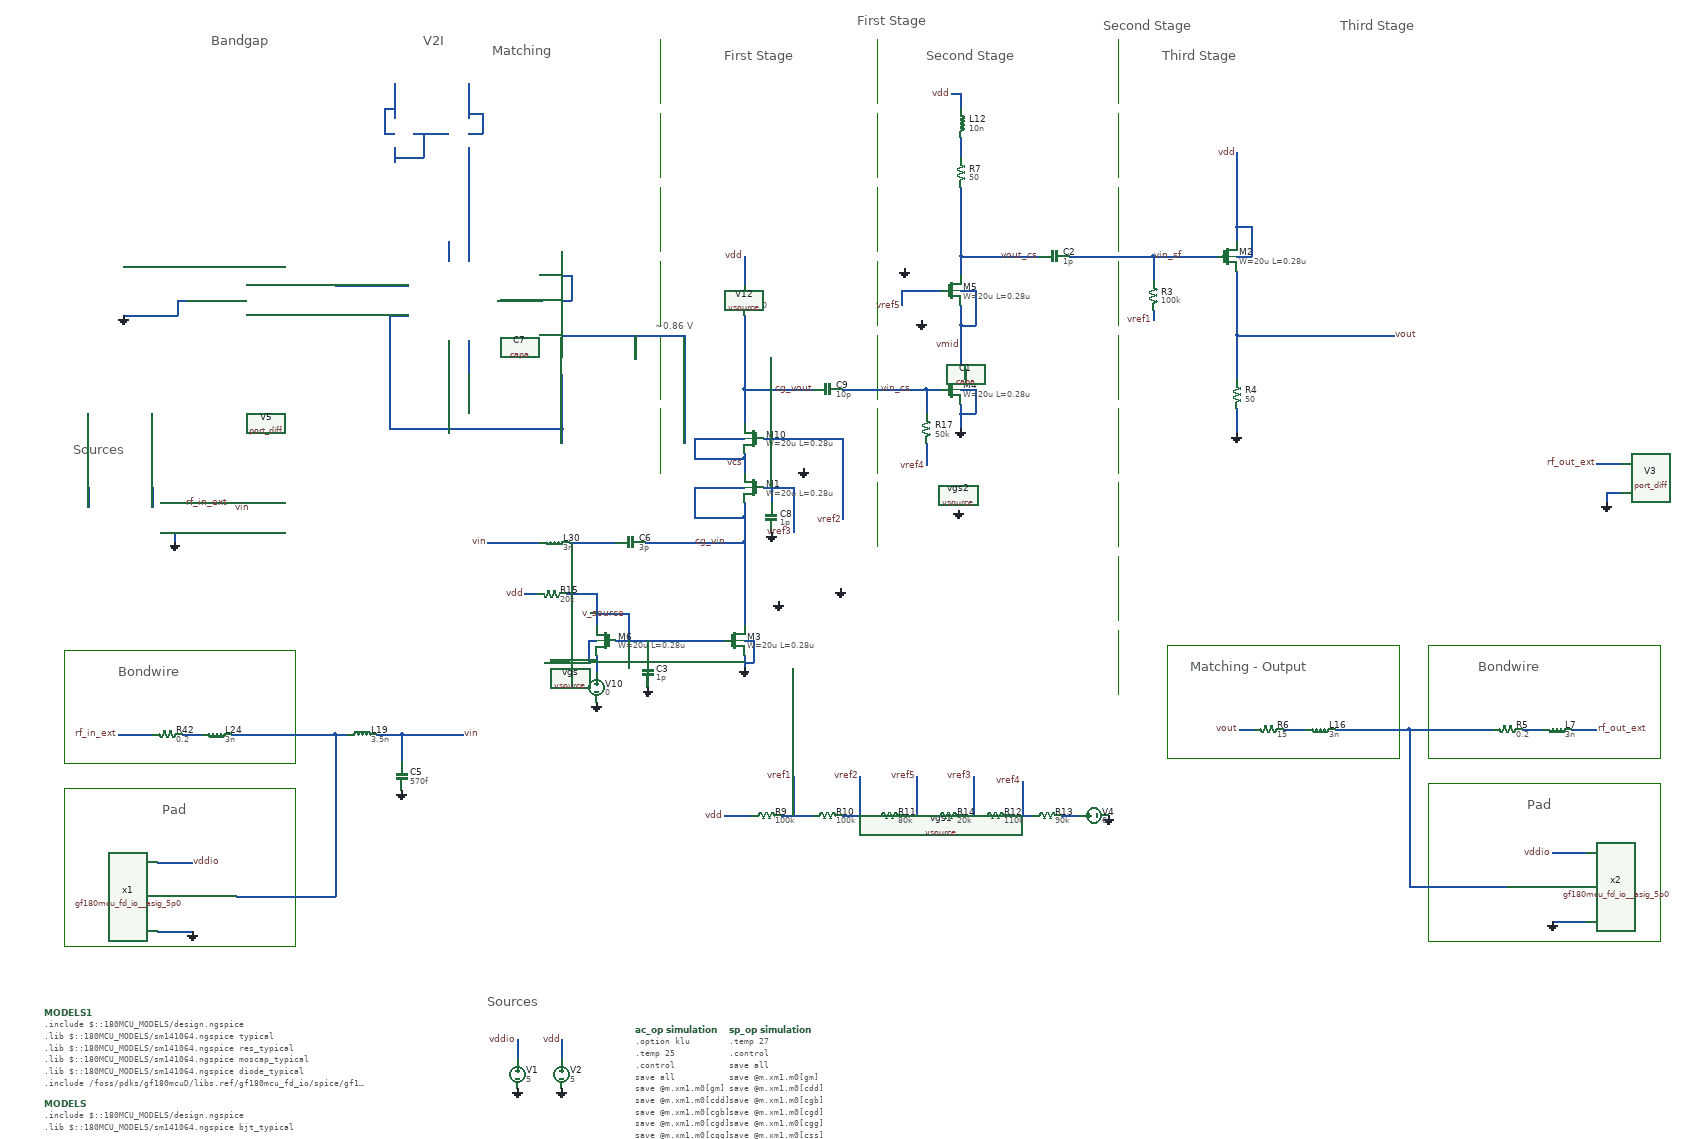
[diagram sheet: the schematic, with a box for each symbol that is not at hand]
v {xschem version=3.4.5 file_version=1.2
}
G {}
K {}
V {}
S {}
E {}
L 4 1330 -2210 1330 -2080 {}
L 4 1330 -2060 1330 -1930 {}
L 4 1330 -1910 1330 -1780 {}
L 4 1330 -1760 1330 -1630 {}
L 4 1330 -1610 1330 -1480 {}
L 4 1330 -2360 1330 -2230 {}
L 4 1770 -2210 1770 -2080 {}
L 4 1770 -2060 1770 -1930 {}
L 4 1770 -1910 1770 -1780 {}
L 4 1770 -1760 1770 -1630 {}
L 4 1770 -1610 1770 -1480 {}
L 4 1770 -1460 1770 -1330 {}
L 4 1770 -2360 1770 -2230 {}
L 4 2260 -2210 2260 -2080 {}
L 4 2260 -2060 2260 -1930 {}
L 4 2260 -1910 2260 -1780 {}
L 4 2260 -1760 2260 -1630 {}
L 4 2260 -1610 2260 -1480 {}
L 4 2260 -2360 2260 -2230 {}
L 4 2260 -1460 2260 -1330 {}
L 4 2260 -1310 2260 -1180 {}
L 4 2260 -1160 2260 -1030 {}
P 4 6 120 -1070 120 -890 590 -890 590 -1120 120 -1120 120 -1070 {}
P 4 6 120 -790 120 -520 590 -520 590 -840 120 -840 120 -790 {}
P 4 6 2890 -1080 2890 -900 3360 -900 3360 -1130 2890 -1130 2890 -1080 {}
P 4 6 2890 -800 2890 -530 3360 -530 3360 -850 2890 -850 2890 -800 {}
P 4 6 2360 -1080 2360 -900 2830 -900 2830 -1130 2360 -1130 2360 -1080 {}
P 4 1 1405 -1355 {}
T {First Stage} 1460 -2340 0 0 0.8 0.8 {}
T {Second Stage} 1870 -2340 0 0 0.8 0.8 {}
T {Third Stage} 2350 -2340 0 0 0.8 0.8 {}
T {Sources} 980 -420 0 0 0.8 0.8 {}
T {Bondwire} 230 -1090 0 0 0.8 0.8 {}
T {Pad} 320 -810 0 0 0.8 0.8 {}
T {Matching} 990 -2350 0 0 0.8 0.8 {}
T {Bondwire} 2990 -1100 0 0 0.8 0.8 {}
T {Pad} 3090 -820 0 0 0.8 0.8 {}
T {Matching - Output} 2405 -1100 0 0 0.8 0.8 {}
N 1040 -330 1040 -290 {lab=vddio}
T {Bandgap} 420 -2370 0 0 0.8 0.8 {}
T {V2I} 850 -2370 0 0 0.8 0.8 {}
T {~0.86 V} 1320 -1790 0 0 0.4 0.4 {}
T {First Stage} 1730 -2410 0 0 0.8 0.8 {}
T {Second Stage} 2230 -2400 0 0 0.8 0.8 {}
T {Third Stage} 2710 -2400 0 0 0.8 0.8 {}
T {Sources} 140 -1540 0 0 0.8 0.8 {}
N 300 -1900 370 -1900 {lab=vdd_5v}
N 240 -1900 300 -1900 {lab=vdd_5v}
N 350 -1830 370 -1830 {lab=0}
N 350 -1830 350 -1810 {lab=0}
N 350 -1810 350 -1800 {lab=0}
N 240 -1800 350 -1800 {lab=0}
N 670 -1860 820 -1860 {lab=vp}
N 900 -1750 900 -1730 {lab=0}
N 940 -1750 940 -1680 {lab=#net1}
N 900 -1950 900 -1910 {lab=vdd_5v}
N 790 -2250 790 -2230 {
lab=vdd_5v}
N 790 -2260 790 -2250 {lab=vdd_5v}
N 780 -1800 820 -1800 {lab=vn}
N 780 -1800 780 -1570 {lab=vn}
N 1000 -1830 1090 -1830 {lab=vref}
N 780 -1570 1130 -1570 {lab=vn}
N 1130 -1930 1130 -1860 {lab=vdd_5v}
N 1130 -1800 1130 -1740 {lab=vdiode}
N 1130 -1680 1130 -1570 {lab=vn}
N 1130 -1570 1130 -1540 {lab=vn}
N 1130 -1760 1380 -1760 {lab=vdiode}
N 1280 -1760 1280 -1710 {lab=vdiode}
N 1380 -1760 1380 -1720 {lab=vdiode}
N 1130 -1830 1150 -1830 {lab=vdd_5v}
N 1150 -1880 1150 -1830 {lab=vdd_5v}
N 1130 -1880 1150 -1880 {lab=vdd_5v}
N 1380 -1720 1380 -1540 {lab=vdiode}
N 830 -2170 900 -2170 {lab=#net2}
N 790 -2230 790 -2200 {lab=vdd_5v}
N 770 -2170 790 -2170 {lab=vdd_5v}
N 770 -2220 770 -2170 {lab=vdd_5v}
N 770 -2220 790 -2220 {lab=vdd_5v}
N 940 -2230 940 -2200 {lab=vdd_5v}
N 940 -2270 940 -2240 {lab=vdd_5v}
N 940 -2240 940 -2230 {lab=vdd_5v}
N 940 -2170 970 -2170 {lab=vdd_5v}
N 970 -2210 970 -2170 {lab=vdd_5v}
N 940 -2210 970 -2210 {lab=vdd_5v}
N 790 -2140 790 -2110 {lab=#net2}
N 850 -2170 850 -2120 {lab=#net2}
N 790 -2120 850 -2120 {lab=#net2}
N 940 -2130 940 -2100 {lab=#net3}
N 940 -2140 940 -2130 {lab=#net3}
N 940 -2100 940 -1910 {lab=#net3}
N 790 -2270 790 -2260 {lab=vdd_5v}
N 300 -1450 300 -1410 {lab=vdd}
N 170 -1450 170 -1410 {lab=vdd_5v}
N 1950 -1690 1950 -1670 {lab=vin
}
N 1500 -1340 1500 -1170 {lab=cg_vin
}
N 1130 -330 1130 -290 {lab=vdd
}
N 1600 -1450 1600 -1360 {lab=vref3
}
N 1540 -1450 1600 -1450 {lab=vref3
}
N 1500 -1920 1500 -1850 {lab=vdd
}
N 1500 -1650 1640 -1650 {lab=cg_vout
}
N 1500 -1800 1500 -1650 {lab=cg_vout
}
N 1700 -1650 1830 -1650 {lab=vin_cs
}
N 1400 -1450 1500 -1450 {lab=cg_vin
}
N 1940 -1600 1940 -1570 {lab=0
}
N 1940 -1650 1970 -1650 {lab=0
}
N 1970 -1650 1970 -1600 {lab=0
}
N 1940 -2160 1940 -2120 {lab=#net1
}
N 1940 -1820 1940 -1780 {lab=vmid
}
N 1940 -1600 1970 -1600 {lab=0
}
N 1940 -1920 2100 -1920 {lab=vout_cs
}
N 1870 -1650 1900 -1650 {lab=vin_cs
}
N 1940 -1780 1940 -1680 {lab=vmid
}
N 1870 -1650 1870 -1600 {lab=vin_cs
}
N 1870 -1540 1870 -1520 {lab=vref4
}
N 1940 -1920 1940 -1880 {lab=vout_cs
}
N 1940 -1850 1970 -1850 {lab=vmid
}
N 1820 -1850 1900 -1850 {lab=vref5
}
N 1820 -1850 1820 -1820 {lab=vref5
}
N 2160 -1920 2310 -1920 {lab=vin_sf
}
N 2330 -1920 2460 -1920 {lab=vin_sf
}
N 2500 -1920 2530 -1920 {lab=vdd
}
N 2500 -1980 2500 -1950 {lab=vdd
spice_ignore=short}
N 2500 -2130 2500 -1980 {lab=vdd
}
N 2330 -1920 2330 -1870 {lab=vin_sf
}
N 2330 -1810 2330 -1790 {lab=vref1
}
N 1940 -2040 1940 -1920 {lab=vout_cs
}
N 1500 -1510 1500 -1480 {lab=vcs
}
N 1400 -1550 1500 -1550 {lab=vcs
}
N 1500 -1650 1500 -1580 {lab=cg_vout
}
N 1540 -1550 1700 -1550 {lab=vref2
}
N 1700 -1550 1700 -1500 {lab=vref2
}
N 1400 -1550 1400 -1510 {lab=vcs
}
N 1400 -1510 1500 -1510 {lab=vcs
}
N 1400 -1450 1400 -1390 {lab=cg_vin
}
N 1400 -1390 1500 -1390 {lab=cg_vin
}
N 1970 -1850 1970 -1780 {lab=vmid
}
N 1940 -1780 1970 -1780 {lab=vmid
}
N 2500 -1610 2500 -1560 {lab=0
}
N 2530 -1980 2530 -1920 {lab=vdd
spice_ignore=short}
N 2500 -1980 2530 -1980 {lab=vdd
}
N 470 -620 670 -620 {lab=#net2
}
N 230 -950 300 -950 {lab=rf_in_ext
}
N 360 -950 400 -950 {lab=#net3
}
N 460 -950 670 -950 {lab=#net2
}
N 315 -1420 365 -1420 {lab=rf_in_ext
}
N 315 -1360 345 -1360 {lab=0
}
N 345 -1360 345 -1340 {lab=0
}
N 1500 -1420 1500 -1390 {lab=cg_vin
}
N 1500 -1390 1500 -1340 {lab=cg_vin
}
N 310 -690 380 -690 {lab=vddio
}
N 310 -550 380 -550 {lab=0
}
N 3080 -960 3120 -960 {lab=#net4
}
N 3180 -960 3230 -960 {lab=rf_out_ext
}
N 3140 -710 3210 -710 {lab=vddio
}
N 3140 -570 3210 -570 {lab=0
}
N 3230 -1500 3280 -1500 {lab=rf_out_ext
}
N 3250 -1440 3280 -1440 {lab=0
}
N 3250 -1440 3250 -1420 {lab=0
}
N 1940 -2230 1940 -2220 {lab=vdd
}
N 1920 -2250 1940 -2250 {lab=vdd
}
N 2500 -1890 2500 -1760 {lab=vout
}
N 2500 -1760 2500 -1670 {lab=vout
}
N 2500 -1760 2820 -1760 {lab=vout
}
N 2850 -640 3050 -640 {lab=#net5
}
N 2700 -960 2850 -960 {lab=#net5
}
N 2595 -960 2640 -960 {lab=#net6
}
N 2505 -960 2535 -960 {lab=vout
}
N 2850 -960 3020 -960 {lab=#net5
}
N 2850 -960 2850 -640 {lab=#net5
}
N 670 -950 695 -950 {lab=#net2
}
N 670 -950 670 -620 {lab=#net2
}
N 805 -950 805 -895 {lab=vin
}
N 805 -950 930 -950 {lab=vin
}
N 1940 -1620 1940 -1600 {lab=0
}
N 1830 -1650 1870 -1650 {lab=vin_cs
}
N 2310 -1920 2330 -1920 {lab=vin_sf
}
N 1500 -1520 1500 -1510 {lab=vcs
}
N 1940 -2060 1940 -2040 {lab=vout_cs
}
N 1940 -2250 1940 -2230 {lab=vdd
}
N 755 -950 805 -950 {lab=vin
}
N 1500 -1110 1500 -1085 {lab=0
}
N 1500 -1140 1520 -1140 {lab=0
}
N 1520 -1140 1520 -1095 {lab=0
}
N 1500 -1095 1520 -1095 {lab=0
}
N 1415 -1140 1460 -1140 {lab=v_source
}
N 1430 -1340 1495 -1340 {lab=cg_vin
}
N 1495 -1340 1500 -1340 {lab=cg_vin
}
N 1240 -1140 1415 -1140 {lab=v_source
}
N 1185 -1140 1200 -1140 {lab=#net7
}
N 1185 -1140 1185 -1100 {lab=#net7
}
N 1185 -1100 1200 -1100 {lab=#net7
}
N 1200 -1210 1200 -1170 {lab=v_source
}
N 1305 -1140 1305 -1105 {lab=v_source
}
N 1200 -1195 1265 -1195 {lab=v_source
}
N 1265 -1195 1265 -1140 {lab=v_source
}
N 1200 -1235 1200 -1210 {lab=v_source
}
N 1140 -1235 1200 -1235 {lab=v_source
}
N 1460 -785 1515 -785 {lab=vdd
}
N 1575 -785 1640 -785 {lab=vref1
}
N 1600 -865 1600 -785 {lab=vref1
}
N 1700 -785 1765 -785 {lab=vref2
}
N 1735 -865 1735 -785 {lab=vref2
}
N 1850 -865 1850 -785 {lab=vref5
}
N 2040 -785 2085 -785 {lab=vref4
}
N 2065 -855 2065 -785 {lab=vref4
}
N 2145 -785 2180 -785 {lab=#net8
}
N 1200 -1110 1200 -1075 {lab=#net7
}
N 1055 -1235 1080 -1235 {lab=vdd
}
N 1700 -1500 1700 -1465 {lab=vref2
}
N 1150 -1340 1150 -1320 {lab=#net9
}
N 1370 -1340 1430 -1340 {lab=cg_vin}
N 1095 -1095 1145 -1095 {lab=#net14
spice_ignore=true}
N 980 -1340 1075 -1340 {lab=vin}
N 1300 -1340 1370 -1340 {lab=cg_vin}
N 1075 -1340 1085 -1340 {lab=vin}
N 1145 -1340 1240 -1340 {lab=#net9}
N 1870 -1520 1870 -1495 {lab=vref4}
N 1700 -1465 1700 -1385 {lab=vref2}
N 1555 -1450 1555 -1420 {lab=vref3}
N 1830 -785 1850 -785 {lab=vref5}
N 1825 -785 1830 -785 {lab=vref5}
N 1850 -785 1885 -785 {lab=vref5}
N 1945 -785 1980 -785 {lab=vref3}
N 1965 -865 1965 -785 {lab=vref3
}
C {title-2.sym} 0 0 0 0 {name=l8 author="Ilir Shala" title="The Silent Owl" rev=1.0 lock=true}
C {vsource.sym} 1040 -260 0 0 {name=V1 value=5 savecurrent=false
}
C {gnd.sym} 380 -550 0 0 {name=l2 lab=0
}
C {lab_pin.sym} 1040 -330 0 0 {name=p10 sig_type=std_logic lab=vddio
}
C {code_shown.sym} 80 -385 0 0 {name=MODELS1 only_toplevel=true
format="tcleval( @value )"
value="
.include $::180MCU_MODELS/design.ngspice
.lib $::180MCU_MODELS/sm141064.ngspice typical
.lib $::180MCU_MODELS/sm141064.ngspice res_typical
.lib $::180MCU_MODELS/sm141064.ngspice moscap_typical
.lib $::180MCU_MODELS/sm141064.ngspice diode_typical
.include /foss/pdks/gf180mcuD/libs.ref/gf180mcu_fd_io/spice/gf180mcu_fd_io.spice
"
spice_ignore=true} C {bandgap.sym} 520 -1760 0 0 {name=x3}
C {gnd.sym} 240 -1800 0 0 {name=l10 lab=0
}
C {devices/code_shown.sym} 80 -200 0 0 {name=MODELS only_toplevel=true
format="tcleval( @value )"
value="
.include $::180MCU_MODELS/design.ngspice
.lib $::180MCU_MODELS/sm141064.ngspice bjt_typical

"}
C {devices/launcher.sym} 1560 -945 0 0 {name=h2
descr="simulate" 
tclcommand="xschem save; xschem netlist; xschem simulate"
}
C {devices/launcher.sym} 1740 -945 0 0 {name=h1
descr="annotate OP" 
tclcommand="set show_hidden_texts 1; xschem annotate_op"
spice_ignore=true}
C {vsource.sym} 1570 -1250 0 0 {name=vgs value=2 savecurrent=false
spice_ignore=true}
C {gnd.sym} 1570 -1220 0 0 {name=l4 lab=0
spice_ignore=true}
C {vsource.sym} 1130 -260 0 0 {name=V2 value=5 savecurrent=false
}
C {gnd.sym} 1130 -230 0 0 {name=l1 lab=0
}
C {res.sym} 1500 -1830 0 0 {name=R1
value=500
footprint=1206
device=resistor
m=1
}
C {symbols/nfet_03v3.sym} 1520 -1450 0 1 {name=M1
L=0.28u
W=20u
nf=1
m=8
ad="'int((nf+1)/2) * W/nf * 0.18u'"
pd="'2*int((nf+1)/2) * (W/nf + 0.18u)'"
as="'int((nf+2)/2) * W/nf * 0.18u'"
ps="'2*int((nf+2)/2) * (W/nf + 0.18u)'"
nrd="'0.18u / W'" nrs="'0.18u / W'"
sa=0 sb=0 sd=0
model=nfet_03v3
spiceprefix=X
}
C {lab_pin.sym} 1130 -330 0 0 {name=p6 sig_type=std_logic lab=vdd
}
C {lab_pin.sym} 1500 -1920 0 0 {name=p7 sig_type=std_logic lab=vdd
}
C {lab_wire.sym} 1465 -1340 2 1 {name=p9 sig_type=std_logic lab=cg_vin
}
C {lab_wire.sym} 1560 -1650 2 0 {name=p38 sig_type=std_logic lab=cg_vout
}
C {capa.sym} 1670 -1650 3 0 {name=C9
m=1
value=10p
footprint=1206
device="ceramic capacitor"
}
C {symbols/nfet_03v3.sym} 1920 -1650 0 0 {name=M4
L=0.28u
W=20u
nf=1
m=10
ad="'int((nf+1)/2) * W/nf * 0.18u'"
pd="'2*int((nf+1)/2) * (W/nf + 0.18u)'"
as="'int((nf+2)/2) * W/nf * 0.18u'"
ps="'2*int((nf+2)/2) * (W/nf + 0.18u)'"
nrd="'0.18u / W'" nrs="'0.18u / W'"
sa=0 sb=0 sd=0
model=nfet_03v3
spiceprefix=X
}
C {res.sym} 1940 -2090 0 0 {name=R7
value=50
footprint=1206
device=resistor
m=1
}
C {lab_pin.sym} 1920 -2250 0 0 {name=p35 sig_type=std_logic lab=vdd
}
C {lab_wire.sym} 2020 -1920 2 0 {name=p36 sig_type=std_logic lab=vout_cs
}
C {gnd.sym} 1940 -1570 0 0 {name=l36 lab=0
}
C {lab_wire.sym} 1840 -1650 0 0 {name=p25 sig_type=std_logic lab=vin_cs
}
C {res.sym} 1870 -1570 0 0 {name=R17
value=50k
footprint=1206
device=resistor
m=1
}
C {symbols/nfet_03v3.sym} 1920 -1850 0 0 {name=M5
L=0.28u
W=20u
nf=1
m=20
ad="'int((nf+1)/2) * W/nf * 0.18u'"
pd="'2*int((nf+1)/2) * (W/nf + 0.18u)'"
as="'int((nf+2)/2) * W/nf * 0.18u'"
ps="'2*int((nf+2)/2) * (W/nf + 0.18u)'"
nrd="'0.18u / W'" nrs="'0.18u / W'"
sa=0 sb=0 sd=0
model=nfet_03v3
spiceprefix=X
}
C {vsource.sym} 1825 -1925 0 0 {name=V12 value=2.2 savecurrent=false
spice_ignore=true}
C {gnd.sym} 1825 -1895 0 0 {name=l23 lab=0
spice_ignore=true}
C {lab_wire.sym} 1940 -1740 0 0 {name=p30 sig_type=std_logic lab=vmid

}
C {capa.sym} 2130 -1920 3 0 {name=C2
m=1
value=1p
footprint=1206
device="ceramic capacitor"
}
C {lab_pin.sym} 2500 -2130 0 0 {name=p8 sig_type=std_logic lab=vdd
}
C {lab_wire.sym} 2390 -1920 0 0 {name=p39 sig_type=std_logic lab=vin_sf
}
C {res.sym} 2330 -1840 0 0 {name=R3
value=100k
footprint=1206
device=resistor
m=1
}
C {symbols/nfet_03v3.sym} 1520 -1550 0 1 {name=M10
L=0.28u
W=20u
nf=1
m=16
ad="'int((nf+1)/2) * W/nf * 0.18u'"
pd="'2*int((nf+1)/2) * (W/nf + 0.18u)'"
as="'int((nf+2)/2) * W/nf * 0.18u'"
ps="'2*int((nf+2)/2) * (W/nf + 0.18u)'"
nrd="'0.18u / W'" nrs="'0.18u / W'"
sa=0 sb=0 sd=0
model=nfet_03v3
spiceprefix=X
}
C {vsource.sym} 1695 -1275 0 0 {name=vgs1 value=3 savecurrent=false
spice_ignore=true}
C {gnd.sym} 1695 -1245 0 0 {name=l35 lab=0
spice_ignore=true}
C {lab_wire.sym} 1500 -1500 2 1 {name=p5 sig_type=std_logic lab=vcs
}
C {symbols/pfet_03v3.sym} 2480 -1920 0 0 {name=M2
L=0.28u
W=20u
nf=1
m=19
ad="'int((nf+1)/2) * W/nf * 0.18u'"
pd="'2*int((nf+1)/2) * (W/nf + 0.18u)'"
as="'int((nf+2)/2) * W/nf * 0.18u'"
ps="'2*int((nf+2)/2) * (W/nf + 0.18u)'"
nrd="'0.18u / W'" nrs="'0.18u / W'"
sa=0 sb=0 sd=0
model=pfet_03v3
spiceprefix=X
}
C {res.sym} 2500 -1640 0 0 {name=R4
value=50
footprint=1206
device=resistor
m=1
}
C {gnd.sym} 2500 -1560 0 0 {name=l5 lab=0
}
C {/foss/designs/theSilentOwl/analog_pad_sp_paramerters/xschem/gf180mcu_fd_io__asig_5p0.sym} 320 -620 0 0 {name=x1 model=gf180mcu_fd_io__asig_5p0
}
C {ind.sym} 430 -950 1 0 {name=L24
m=1
value=3n
footprint=1206
device=inductor
}
C {res.sym} 330 -950 1 0 {name=R42
value=0.2
footprint=1206
device=resistor
m=1
}
C {lab_pin.sym} 230 -950 0 0 {name=p1 sig_type=std_logic lab=rf_in_ext
}
C {gnd.sym} 345 -1340 0 0 {name=l25 lab=0
}
C {/foss/designs/theSilentOwl/analog_pad_sp_paramerters/xschem/port_diff.sym} 315 -1390 0 0 {name=V5 portnum=1 Z0=50 DCval=0 ACmag=1 ACphase=0 TRANval="PWL(0 0)"
}
C {lab_pin.sym} 930 -950 2 0 {name=p3 sig_type=std_logic lab=vin
}
C {lab_wire.sym} 980 -1340 2 1 {name=p4 sig_type=std_logic lab=vin
}
C {lab_pin.sym} 3140 -710 2 1 {name=p12 sig_type=std_logic lab=vddio
}
C {/foss/designs/theSilentOwl/analog_pad_sp_paramerters/xschem/gf180mcu_fd_io__asig_5p0.sym} 3200 -640 0 1 {name=x2 model=gf180mcu_fd_io__asig_5p0
}
C {ind.sym} 3150 -960 1 0 {name=L7
m=1
value=3n
footprint=1206
device=inductor
}
C {res.sym} 3050 -960 1 0 {name=R5
value=0.2
footprint=1206
device=resistor
m=1
}
C {lab_pin.sym} 3230 -960 2 0 {name=p14 sig_type=std_logic lab=rf_out_ext
}
C {lab_wire.sym} 2820 -1760 2 0 {name=p17 sig_type=std_logic lab=vout
}
C {lab_pin.sym} 3230 -1500 0 0 {name=p18 sig_type=std_logic lab=rf_out_ext
}
C {gnd.sym} 3250 -1420 0 0 {name=l11 lab=0
}
C {/foss/designs/theSilentOwl/analog_pad_sp_paramerters/xschem/port_diff.sym} 3280 -1470 0 1 {name=V3 portnum=2 Z0=50 DCval=0 ACmag=0 ACphase=0 TRANval="PWL(0 0)"
}
C {code.sym} 1280 -350 0 0 {name="ac_op simulation" only_toplevel=true 
value="

.option klu
.temp 25
.control

save all
save @m.xm1.m0[gm]
save @m.xm1.m0[cdd]
save @m.xm1.m0[cgb]
save @m.xm1.m0[cgd]
save @m.xm1.m0[cgg]
save @m.xm1.m0[css]
save @m.xm1.m0[cgs]
save @m.xm1.m0[id]
save @m.xm1.m0[vgs]

save @m.xm2.m0[id]
save @m.xm2.m0[gm]

save @m.xm3.m0[id]
save @m.xm3.m0[gm]
save @m.xm3.m0[gds]

save @m.xm4.m0[id]
save @m.xm4.m0[gm]

save @m.xm5.m0[id]
save @m.xm5.m0[gm]

save @m.xm8.m0[id]
save @m.xm8.m0[gm]

save @m.xm9.m0[id]
save @m.xm9.m0[gm]

save @m.xm10.m0[id]
save @m.xm10.m0[gm]

op
write LNA_sim.raw
set appendwrite

ac dec 20 1 20e9
let A_fs = db(v(cg_vout)/v(cg_vin))
let A_ss = db(v(vout_cs)/v(vin_cs))
let A_ts = db(v(vin_sf)/v(vout_sf))
let A = db(v(vout_sf)/v(cg_vin))
let A_fs_ss = db(v(vout_cs)/v(cg_vin))
*let vo_phase_margin = phase(v(vo)) *180/pi+180
*meas ac A0 find vo_mag at=1k
*meas ac UGF when vo_mag=1 fall=1
*meas ac PM find vo_phase_margin when vo_mag=1
*echo $&A0 $&UGF $&PM
*echo $&A0
*echo $plots
*plot A_fs A_ss A_ts A
plot A_ts
plot A_fs_ss
remzerovec
write LNA_sim.raw

.endc
"
spice_ignore=true}
C {code.sym} 1470 -350 0 0 {name="sp_op simulation" only_toplevel=true 
value="

.temp 27
.control

save all
save @m.xm1.m0[gm]
save @m.xm1.m0[cdd]
save @m.xm1.m0[cgb]
save @m.xm1.m0[cgd]
save @m.xm1.m0[cgg]
save @m.xm1.m0[css]
save @m.xm1.m0[cgs]
save @m.xm1.m0[id]
save @m.xm1.m0[vgs]

save @m.xm2.m0[id]
save @m.xm2.m0[gm]

save @m.xm3.m0[id]
save @m.xm3.m0[gm]
save @m.xm3.m0[gds]

save @m.xm4.m0[id]
save @m.xm4.m0[gm]

save @m.xm5.m0[id]
save @m.xm5.m0[gm]

save @m.xm8.m0[id]
save @m.xm8.m0[gm]

save @m.xm9.m0[id]
save @m.xm9.m0[gm]

save @m.xm10.m0[id]
save @m.xm10.m0[gm]

op
write LNA_sim.raw
set appendwrite

*set spnum = 1

sp lin 500 100e6 10e9 1
write LNA_sim.raw

let zin = 50*(1+s_1_1)/(1-s_1_1)
let zout = 50*(1+s_2_2)/(1-s_2_2)
*plot mag(zin)
*plot ph(zin)

plot vdb(s_1_1) vdb(s_2_2)
plot vdb(s_2_1)
plot nf NFmin
*plot Im(zin) Re(zin)
plot Im(zout) Re(zout)
let Rbase = 50
wrs2p /foss/designs/thesilentowl/xschem/LNA_sim.s2p

*quit
.endc
"
}
C {devices/launcher.sym} 1970 -945 0 0 {name=h5
descr="waveform" 
tclcommand="xschem raw_read $netlist_dir/lna_first_stage.raw sp"
spice_ignore=true}
C {ind.sym} 1940 -2190 0 0 {name=L12
m=1
value=10n
footprint=1206
device=inductor
}
C {lab_wire.sym} 2505 -960 0 0 {name=p20 sig_type=std_logic lab=vout
}
C {gnd.sym} 3140 -570 0 0 {name=l14 lab=0
}
C {gnd.sym} 1040 -230 0 0 {name=l15 lab=0
}
C {lab_pin.sym} 380 -690 2 0 {name=p13 sig_type=std_logic lab=vddio
}
C {ind.sym} 2670 -960 1 0 {name=L16
m=1
value=3n
footprint=1206
device=inductor
}
C {res.sym} 2565 -960 1 0 {name=R6
value=15
footprint=1206
device=resistor
m=1
}
C {capa.sym} 805 -865 0 0 {name=C5
m=1
value=570f
footprint=1206
device="ceramic capacitor"
}
C {ind.sym} 725 -950 3 0 {name=L19
m=1
value=3.5n
footprint=1206
device=inductor
}
C {gnd.sym} 805 -835 0 0 {name=l20 lab=0
}
C {symbols/nfet_03v3.sym} 1480 -1140 0 0 {name=M3
L=0.28u
W=20u
nf=1
m=16
ad="'int((nf+1)/2) * W/nf * 0.18u'"
pd="'2*int((nf+1)/2) * (W/nf + 0.18u)'"
as="'int((nf+2)/2) * W/nf * 0.18u'"
ps="'2*int((nf+2)/2) * (W/nf + 0.18u)'"
nrd="'0.18u / W'" nrs="'0.18u / W'"
sa=0 sb=0 sd=0
model=nfet_03v3
spiceprefix=X
}
C {gnd.sym} 1500 -1085 0 0 {name=l3 lab=0
}
C {symbols/nfet_03v3.sym} 1220 -1140 0 1 {name=M6
L=0.28u
W=20u
nf=1
m=1
ad="'int((nf+1)/2) * W/nf * 0.18u'"
pd="'2*int((nf+1)/2) * (W/nf + 0.18u)'"
as="'int((nf+2)/2) * W/nf * 0.18u'"
ps="'2*int((nf+2)/2) * (W/nf + 0.18u)'"
nrd="'0.18u / W'" nrs="'0.18u / W'"
sa=0 sb=0 sd=0
model=nfet_03v3
spiceprefix=X
}
C {capa.sym} 1305 -1075 2 0 {name=C3
m=1
value=1p
footprint=1206
device="ceramic capacitor"
}
C {gnd.sym} 1305 -1045 0 0 {name=l10 lab=0
}
C {lab_pin.sym} 1260 -1195 1 0 {name=p27 sig_type=std_logic lab=v_source
}
C {lab_wire.sym} 1600 -865 1 1 {name=p29 sig_type=std_logic lab=vref1
}
C {lab_pin.sym} 1460 -785 3 0 {name=p31 sig_type=std_logic lab=vdd
}
C {res.sym} 1545 -785 3 0 {name=R9
value=100k
footprint=1206
device=resistor
m=1
}
C {res.sym} 1670 -785 3 0 {name=R10
value=100k
footprint=1206
device=resistor
m=1
}
C {lab_wire.sym} 1735 -865 1 1 {name=p32 sig_type=std_logic lab=vref2
}
C {res.sym} 1795 -785 3 0 {name=R11
value=80k
footprint=1206
device=resistor
m=1
}
C {lab_wire.sym} 1850 -865 1 1 {name=p33 sig_type=std_logic lab=vref5
}
C {res.sym} 2115 -785 3 0 {name=R13
value=90k
footprint=1206
device=resistor
m=1
}
C {lab_wire.sym} 2065 -855 1 1 {name=p34 sig_type=std_logic lab=vref4
}
C {gnd.sym} 2240 -785 3 0 {name=l9 lab=0
}
C {vsource.sym} 2210 -785 3 0 {name=V4 value=0 savecurrent=false
}
C {gnd.sym} 1200 -1015 0 0 {name=l26 lab=0
}
C {vsource.sym} 1200 -1045 0 0 {name=V10 value=0 savecurrent=false
}
C {lab_pin.sym} 1055 -1235 0 0 {name=p26 sig_type=std_logic lab=vdd
}
C {res.sym} 1110 -1235 1 0 {name=R15
value=20k
footprint=1206
device=resistor
m=1
}
C {lab_wire.sym} 1870 -1495 1 1 {name=p40 sig_type=std_logic lab=vref4
}
C {capa.sym} 1270 -1340 3 0 {name=C6
m=1
value=3p
footprint=1206
device="ceramic capacitor"
}
C {lab_pin.sym} 365 -1420 2 0 {name=p2 sig_type=std_logic lab=rf_in_ext
}
C {vsource.sym} 1935 -1435 0 0 {name=vgs2 value=0.9 savecurrent=false
spice_ignore=true}
C {gnd.sym} 1935 -1405 0 0 {name=l21 lab=0
spice_ignore=true}
C {lab_pin.sym} 465 -1410 2 0 {name=p41 sig_type=std_logic lab=vin
spice_ignore=true}
C {ind.sym} 1115 -1340 1 0 {name=L30
m=1
value=3n
footprint=1206
device=inductor
}
C {lab_wire.sym} 2330 -1790 1 1 {name=p37 sig_type=std_logic lab=vref1
}
C {capa.sym} 1620 -1520 0 0 {name=C7
m=1
value=1p
footprint=1206
device="ceramic capacitor"
}
C {gnd.sym} 1620 -1490 0 0 {name=l31 lab=0
}
C {lab_wire.sym} 1700 -1385 1 1 {name=p42 sig_type=std_logic lab=vref2
}
C {capa.sym} 1555 -1390 0 0 {name=C8
m=1
value=1p
footprint=1206
device="ceramic capacitor"
}
C {gnd.sym} 1555 -1360 0 0 {name=l32 lab=0
}
C {lab_wire.sym} 1600 -1360 1 1 {name=p43 sig_type=std_logic lab=vref3
}
C {lab_wire.sym} 1820 -1820 1 1 {name=p44 sig_type=std_logic lab=vref5
}
C {capa.sym} 1860 -1820 0 0 {name=C1
m=1
value=1p
footprint=1206
device="ceramic capacitor"
}
C {gnd.sym} 1860 -1790 0 0 {name=l27 lab=0
}
C {res.sym} 1915 -785 3 0 {name=R14
value=20k
footprint=1206
device=resistor
m=1
}
C {res.sym} 2010 -785 3 0 {name=R12
value=110k
footprint=1206
device=resistor
m=1
}
C {lab_wire.sym} 1965 -865 1 1 {name=p45 sig_type=std_logic lab=vref3
}
